VERSION 5.6 ;
BUSBITCHARS "[]" ;
DIVIDERCHAR "/" ;

PROPERTYDEFINITIONS
  LIBRARY LEF58_CELLEDGESPACINGTABLE STRING
    "CELLEDGESPACINGTABLE
      EDGETYPE VERTICAL_EDGE_2 VERTICAL_EDGE_2 0.5 ; " ;
END PROPERTYDEFINITIONS

# Asymmetric cell edge types: mirroring about Y moves the VERTICAL_EDGE_2
# edge from the right side of the cell to the left side.
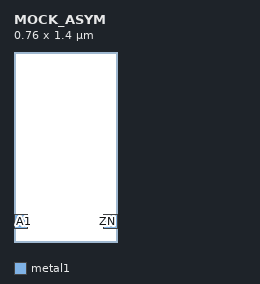
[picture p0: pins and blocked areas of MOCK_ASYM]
MACRO MOCK_ASYM
  CLASS CORE ;
  ORIGIN 0 0 ;
  SIZE 0.76 BY 1.4 ;
  SYMMETRY X Y ;
  SITE FreePDK45_38x28_10R_NP_162NW_34O ;
  PROPERTY LEF58_EDGETYPE "
    EDGETYPE LEFT VERTICAL_EDGE_1 ;
    EDGETYPE RIGHT VERTICAL_EDGE_2 ; " ;
  PIN A1
    DIRECTION INPUT ;
    USE SIGNAL ;
    PORT
      LAYER metal1 ;
        RECT 0 0.1 0.1 0.2 ;
    END
  END A1
  PIN ZN
    DIRECTION OUTPUT ;
    USE SIGNAL ;
    PORT
      LAYER metal1 ;
        RECT 0.66 0.1 0.76 0.2 ;
    END
  END ZN
  PIN VDD
  END VDD
  PIN VSS
  END VSS
END MOCK_ASYM
